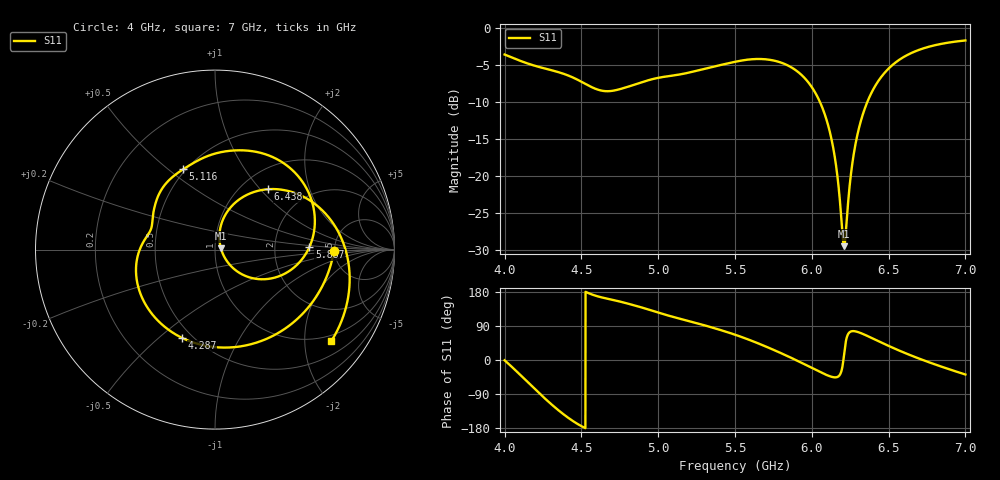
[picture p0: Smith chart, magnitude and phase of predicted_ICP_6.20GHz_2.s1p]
! ICP-predicted S11, target max centred GHz at -10 dB. Complex ensemble mean (passive and causal);
! its |S11| can differ slightly from the dB-domain mean reported in designs.csv.
!  Air_gap = 2.02mm
!  W_Patch = 14.12mm
!  L_Patch = 18.69mm
!  Sx = 1.53mm
!  Sy = 3.08mm
!  W_Patch1 = 11.06mm
!  WS = 1.4mm
!  Curve_Amp1 = 3.3mm
!  Extra = 7.53mm
# GHz S MA R 50
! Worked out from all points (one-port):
!   3001 points, 4 GHz to 7 GHz, reference 50 ohm
!   lowest |S11| = -29.5 dB at 6.21 GHz (marker M1), VSWR 1.07, Z = 53.4 + j0.883 ohm
!   |S11| at or under -10 dB: 6.053 GHz to 6.361 GHz (307.9 MHz wide, 4.96 % of centre)
!   S11 on the Smith chart (normalised r, x): 4 GHz: 4.92, -0.15; 4.287 GHz: 0.44, -0.60; 5.116 GHz: 0.48, +0.56; 5.887 GHz: 3.22, +0.14; 6.438 GHz: 1.31, +1.10; 7 GHz: 0.83, -2.65
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4  0.6625 -0.7
4.07  0.6189 -26.9
4.153  0.575 -59.3
4.218  0.5483 -84.7
4.287  0.5249 -110.6
4.375  0.4945 -140.6
4.537  0.4138 178.1
4.75  0.3865 154.3
4.928  0.4417 134.3
5.116  0.4813 111.7
5.125  0.483 110.7
5.5  0.5917 66.8
5.721  0.6115 32.1
5.875  0.5365 4.0
5.887  0.5266 1.7
6.002  0.3962 -21.2
6.099  0.2343 -40.0
6.154  0.1257 -45.9
6.199  0.04161 -18.4
6.21  0.0336 14.2
6.222  0.04233 49.7
6.25  0.09318 74.4
6.281  0.1572 75.8
6.321  0.2389 70.7
6.438  0.4463 48.9
6.625  0.6604 15.4
6.8  0.7652 -11.3
7  0.8248 -38.3
